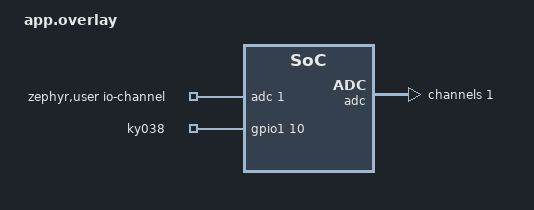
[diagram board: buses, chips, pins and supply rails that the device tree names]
/ {
    aliases {
        ky038 = &ky038;
    };

    zephyr,user {
        io-channels = <&adc 1>;
    };

    sensors {
        compatible = "gpio-keys";

        ky038: ky038 {
            gpios = <&gpio1 10 GPIO_ACTIVE_HIGH>;
        };
    };
};

&adc {
    status = "okay";
    #address-cells = <1>;
    #size-cells = <0>;

    channel@1 {
        reg = <1>;
        zephyr,gain = "ADC_GAIN_1_6";
        zephyr,reference = "ADC_REF_INTERNAL";
        zephyr,acquisition-time = <ADC_ACQ_TIME_DEFAULT>;
        zephyr,input-positive = <NRF_SAADC_AIN1>;
        zephyr,resolution = <12>;
    };
};
